# Generated by FakeRAM 2.0
VERSION 5.7 ;
BUSBITCHARS "[]" ;
PROPERTYDEFINITIONS
  MACRO width INTEGER ;
  MACRO depth INTEGER ;
  MACRO banks INTEGER ;
END PROPERTYDEFINITIONS
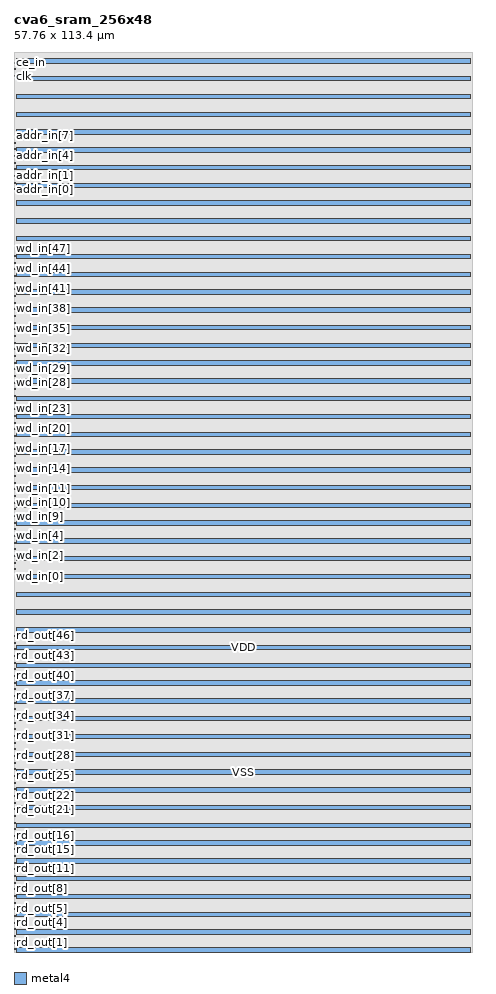
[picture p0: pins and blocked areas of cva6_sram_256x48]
MACRO cva6_sram_256x48
  PROPERTY width 48 ;
  PROPERTY depth 256 ;
  PROPERTY banks 1 ;
  FOREIGN cva6_sram_256x48 0 0 ;
  SYMMETRY X Y R90 ;
  SIZE 57.7600 BY 113.4000 ;
  CLASS BLOCK ;
  PIN rd_out[0]
    DIRECTION OUTPUT ;
    USE SIGNAL ;
    PORT
      LAYER metal4 ;
      RECT 0.00000 0.28000 0.14000 0.42000 ;
    END
  END rd_out[0]
  PIN rd_out[1]
    DIRECTION OUTPUT ;
    USE SIGNAL ;
    PORT
      LAYER metal4 ;
      RECT 0.00000 1.12000 0.14000 1.26000 ;
    END
  END rd_out[1]
  PIN rd_out[2]
    DIRECTION OUTPUT ;
    USE SIGNAL ;
    PORT
      LAYER metal4 ;
      RECT 0.00000 1.96000 0.14000 2.10000 ;
    END
  END rd_out[2]
  PIN rd_out[3]
    DIRECTION OUTPUT ;
    USE SIGNAL ;
    PORT
      LAYER metal4 ;
      RECT 0.00000 2.80000 0.14000 2.94000 ;
    END
  END rd_out[3]
  PIN rd_out[4]
    DIRECTION OUTPUT ;
    USE SIGNAL ;
    PORT
      LAYER metal4 ;
      RECT 0.00000 3.64000 0.14000 3.78000 ;
    END
  END rd_out[4]
  PIN rd_out[5]
    DIRECTION OUTPUT ;
    USE SIGNAL ;
    PORT
      LAYER metal4 ;
      RECT 0.00000 4.48000 0.14000 4.62000 ;
    END
  END rd_out[5]
  PIN rd_out[6]
    DIRECTION OUTPUT ;
    USE SIGNAL ;
    PORT
      LAYER metal4 ;
      RECT 0.00000 5.32000 0.14000 5.46000 ;
    END
  END rd_out[6]
  PIN rd_out[7]
    DIRECTION OUTPUT ;
    USE SIGNAL ;
    PORT
      LAYER metal4 ;
      RECT 0.00000 6.16000 0.14000 6.30000 ;
    END
  END rd_out[7]
  PIN rd_out[8]
    DIRECTION OUTPUT ;
    USE SIGNAL ;
    PORT
      LAYER metal4 ;
      RECT 0.00000 7.00000 0.14000 7.14000 ;
    END
  END rd_out[8]
  PIN rd_out[9]
    DIRECTION OUTPUT ;
    USE SIGNAL ;
    PORT
      LAYER metal4 ;
      RECT 0.00000 7.84000 0.14000 7.98000 ;
    END
  END rd_out[9]
  PIN rd_out[10]
    DIRECTION OUTPUT ;
    USE SIGNAL ;
    PORT
      LAYER metal4 ;
      RECT 0.00000 8.68000 0.14000 8.82000 ;
    END
  END rd_out[10]
  PIN rd_out[11]
    DIRECTION OUTPUT ;
    USE SIGNAL ;
    PORT
      LAYER metal4 ;
      RECT 0.00000 9.52000 0.14000 9.66000 ;
    END
  END rd_out[11]
  PIN rd_out[12]
    DIRECTION OUTPUT ;
    USE SIGNAL ;
    PORT
      LAYER metal4 ;
      RECT 0.00000 10.36000 0.14000 10.50000 ;
    END
  END rd_out[12]
  PIN rd_out[13]
    DIRECTION OUTPUT ;
    USE SIGNAL ;
    PORT
      LAYER metal4 ;
      RECT 0.00000 11.20000 0.14000 11.34000 ;
    END
  END rd_out[13]
  PIN rd_out[14]
    DIRECTION OUTPUT ;
    USE SIGNAL ;
    PORT
      LAYER metal4 ;
      RECT 0.00000 12.04000 0.14000 12.18000 ;
    END
  END rd_out[14]
  PIN rd_out[15]
    DIRECTION OUTPUT ;
    USE SIGNAL ;
    PORT
      LAYER metal4 ;
      RECT 0.00000 12.88000 0.14000 13.02000 ;
    END
  END rd_out[15]
  PIN rd_out[16]
    DIRECTION OUTPUT ;
    USE SIGNAL ;
    PORT
      LAYER metal4 ;
      RECT 0.00000 13.72000 0.14000 13.86000 ;
    END
  END rd_out[16]
  PIN rd_out[17]
    DIRECTION OUTPUT ;
    USE SIGNAL ;
    PORT
      LAYER metal4 ;
      RECT 0.00000 14.56000 0.14000 14.70000 ;
    END
  END rd_out[17]
  PIN rd_out[18]
    DIRECTION OUTPUT ;
    USE SIGNAL ;
    PORT
      LAYER metal4 ;
      RECT 0.00000 15.40000 0.14000 15.54000 ;
    END
  END rd_out[18]
  PIN rd_out[19]
    DIRECTION OUTPUT ;
    USE SIGNAL ;
    PORT
      LAYER metal4 ;
      RECT 0.00000 16.24000 0.14000 16.38000 ;
    END
  END rd_out[19]
  PIN rd_out[20]
    DIRECTION OUTPUT ;
    USE SIGNAL ;
    PORT
      LAYER metal4 ;
      RECT 0.00000 17.08000 0.14000 17.22000 ;
    END
  END rd_out[20]
  PIN rd_out[21]
    DIRECTION OUTPUT ;
    USE SIGNAL ;
    PORT
      LAYER metal4 ;
      RECT 0.00000 17.92000 0.14000 18.06000 ;
    END
  END rd_out[21]
  PIN rd_out[22]
    DIRECTION OUTPUT ;
    USE SIGNAL ;
    PORT
      LAYER metal4 ;
      RECT 0.00000 18.76000 0.14000 18.90000 ;
    END
  END rd_out[22]
  PIN rd_out[23]
    DIRECTION OUTPUT ;
    USE SIGNAL ;
    PORT
      LAYER metal4 ;
      RECT 0.00000 19.60000 0.14000 19.74000 ;
    END
  END rd_out[23]
  PIN rd_out[24]
    DIRECTION OUTPUT ;
    USE SIGNAL ;
    PORT
      LAYER metal4 ;
      RECT 0.00000 20.44000 0.14000 20.58000 ;
    END
  END rd_out[24]
  PIN rd_out[25]
    DIRECTION OUTPUT ;
    USE SIGNAL ;
    PORT
      LAYER metal4 ;
      RECT 0.00000 21.28000 0.14000 21.42000 ;
    END
  END rd_out[25]
  PIN rd_out[26]
    DIRECTION OUTPUT ;
    USE SIGNAL ;
    PORT
      LAYER metal4 ;
      RECT 0.00000 22.12000 0.14000 22.26000 ;
    END
  END rd_out[26]
  PIN rd_out[27]
    DIRECTION OUTPUT ;
    USE SIGNAL ;
    PORT
      LAYER metal4 ;
      RECT 0.00000 22.96000 0.14000 23.10000 ;
    END
  END rd_out[27]
  PIN rd_out[28]
    DIRECTION OUTPUT ;
    USE SIGNAL ;
    PORT
      LAYER metal4 ;
      RECT 0.00000 23.80000 0.14000 23.94000 ;
    END
  END rd_out[28]
  PIN rd_out[29]
    DIRECTION OUTPUT ;
    USE SIGNAL ;
    PORT
      LAYER metal4 ;
      RECT 0.00000 24.64000 0.14000 24.78000 ;
    END
  END rd_out[29]
  PIN rd_out[30]
    DIRECTION OUTPUT ;
    USE SIGNAL ;
    PORT
      LAYER metal4 ;
      RECT 0.00000 25.48000 0.14000 25.62000 ;
    END
  END rd_out[30]
  PIN rd_out[31]
    DIRECTION OUTPUT ;
    USE SIGNAL ;
    PORT
      LAYER metal4 ;
      RECT 0.00000 26.32000 0.14000 26.46000 ;
    END
  END rd_out[31]
  PIN rd_out[32]
    DIRECTION OUTPUT ;
    USE SIGNAL ;
    PORT
      LAYER metal4 ;
      RECT 0.00000 27.16000 0.14000 27.30000 ;
    END
  END rd_out[32]
  PIN rd_out[33]
    DIRECTION OUTPUT ;
    USE SIGNAL ;
    PORT
      LAYER metal4 ;
      RECT 0.00000 28.00000 0.14000 28.14000 ;
    END
  END rd_out[33]
  PIN rd_out[34]
    DIRECTION OUTPUT ;
    USE SIGNAL ;
    PORT
      LAYER metal4 ;
      RECT 0.00000 28.84000 0.14000 28.98000 ;
    END
  END rd_out[34]
  PIN rd_out[35]
    DIRECTION OUTPUT ;
    USE SIGNAL ;
    PORT
      LAYER metal4 ;
      RECT 0.00000 29.68000 0.14000 29.82000 ;
    END
  END rd_out[35]
  PIN rd_out[36]
    DIRECTION OUTPUT ;
    USE SIGNAL ;
    PORT
      LAYER metal4 ;
      RECT 0.00000 30.52000 0.14000 30.66000 ;
    END
  END rd_out[36]
  PIN rd_out[37]
    DIRECTION OUTPUT ;
    USE SIGNAL ;
    PORT
      LAYER metal4 ;
      RECT 0.00000 31.36000 0.14000 31.50000 ;
    END
  END rd_out[37]
  PIN rd_out[38]
    DIRECTION OUTPUT ;
    USE SIGNAL ;
    PORT
      LAYER metal4 ;
      RECT 0.00000 32.20000 0.14000 32.34000 ;
    END
  END rd_out[38]
  PIN rd_out[39]
    DIRECTION OUTPUT ;
    USE SIGNAL ;
    PORT
      LAYER metal4 ;
      RECT 0.00000 33.04000 0.14000 33.18000 ;
    END
  END rd_out[39]
  PIN rd_out[40]
    DIRECTION OUTPUT ;
    USE SIGNAL ;
    PORT
      LAYER metal4 ;
      RECT 0.00000 33.88000 0.14000 34.02000 ;
    END
  END rd_out[40]
  PIN rd_out[41]
    DIRECTION OUTPUT ;
    USE SIGNAL ;
    PORT
      LAYER metal4 ;
      RECT 0.00000 34.72000 0.14000 34.86000 ;
    END
  END rd_out[41]
  PIN rd_out[42]
    DIRECTION OUTPUT ;
    USE SIGNAL ;
    PORT
      LAYER metal4 ;
      RECT 0.00000 35.56000 0.14000 35.70000 ;
    END
  END rd_out[42]
  PIN rd_out[43]
    DIRECTION OUTPUT ;
    USE SIGNAL ;
    PORT
      LAYER metal4 ;
      RECT 0.00000 36.40000 0.14000 36.54000 ;
    END
  END rd_out[43]
  PIN rd_out[44]
    DIRECTION OUTPUT ;
    USE SIGNAL ;
    PORT
      LAYER metal4 ;
      RECT 0.00000 37.24000 0.14000 37.38000 ;
    END
  END rd_out[44]
  PIN rd_out[45]
    DIRECTION OUTPUT ;
    USE SIGNAL ;
    PORT
      LAYER metal4 ;
      RECT 0.00000 38.08000 0.14000 38.22000 ;
    END
  END rd_out[45]
  PIN rd_out[46]
    DIRECTION OUTPUT ;
    USE SIGNAL ;
    PORT
      LAYER metal4 ;
      RECT 0.00000 38.92000 0.14000 39.06000 ;
    END
  END rd_out[46]
  PIN rd_out[47]
    DIRECTION OUTPUT ;
    USE SIGNAL ;
    PORT
      LAYER metal4 ;
      RECT 0.00000 39.76000 0.14000 39.90000 ;
    END
  END rd_out[47]
  PIN wd_in[0]
    DIRECTION INPUT ;
    USE SIGNAL ;
    PORT
      LAYER metal4 ;
      RECT 0.00000 48.16000 0.14000 48.30000 ;
    END
  END wd_in[0]
  PIN wd_in[1]
    DIRECTION INPUT ;
    USE SIGNAL ;
    PORT
      LAYER metal4 ;
      RECT 0.00000 49.00000 0.14000 49.14000 ;
    END
  END wd_in[1]
  PIN wd_in[2]
    DIRECTION INPUT ;
    USE SIGNAL ;
    PORT
      LAYER metal4 ;
      RECT 0.00000 49.84000 0.14000 49.98000 ;
    END
  END wd_in[2]
  PIN wd_in[3]
    DIRECTION INPUT ;
    USE SIGNAL ;
    PORT
      LAYER metal4 ;
      RECT 0.00000 50.68000 0.14000 50.82000 ;
    END
  END wd_in[3]
  PIN wd_in[4]
    DIRECTION INPUT ;
    USE SIGNAL ;
    PORT
      LAYER metal4 ;
      RECT 0.00000 51.52000 0.14000 51.66000 ;
    END
  END wd_in[4]
  PIN wd_in[5]
    DIRECTION INPUT ;
    USE SIGNAL ;
    PORT
      LAYER metal4 ;
      RECT 0.00000 52.36000 0.14000 52.50000 ;
    END
  END wd_in[5]
  PIN wd_in[6]
    DIRECTION INPUT ;
    USE SIGNAL ;
    PORT
      LAYER metal4 ;
      RECT 0.00000 53.20000 0.14000 53.34000 ;
    END
  END wd_in[6]
  PIN wd_in[7]
    DIRECTION INPUT ;
    USE SIGNAL ;
    PORT
      LAYER metal4 ;
      RECT 0.00000 54.04000 0.14000 54.18000 ;
    END
  END wd_in[7]
  PIN wd_in[8]
    DIRECTION INPUT ;
    USE SIGNAL ;
    PORT
      LAYER metal4 ;
      RECT 0.00000 54.88000 0.14000 55.02000 ;
    END
  END wd_in[8]
  PIN wd_in[9]
    DIRECTION INPUT ;
    USE SIGNAL ;
    PORT
      LAYER metal4 ;
      RECT 0.00000 55.72000 0.14000 55.86000 ;
    END
  END wd_in[9]
  PIN wd_in[10]
    DIRECTION INPUT ;
    USE SIGNAL ;
    PORT
      LAYER metal4 ;
      RECT 0.00000 56.56000 0.14000 56.70000 ;
    END
  END wd_in[10]
  PIN wd_in[11]
    DIRECTION INPUT ;
    USE SIGNAL ;
    PORT
      LAYER metal4 ;
      RECT 0.00000 57.40000 0.14000 57.54000 ;
    END
  END wd_in[11]
  PIN wd_in[12]
    DIRECTION INPUT ;
    USE SIGNAL ;
    PORT
      LAYER metal4 ;
      RECT 0.00000 58.24000 0.14000 58.38000 ;
    END
  END wd_in[12]
  PIN wd_in[13]
    DIRECTION INPUT ;
    USE SIGNAL ;
    PORT
      LAYER metal4 ;
      RECT 0.00000 59.08000 0.14000 59.22000 ;
    END
  END wd_in[13]
  PIN wd_in[14]
    DIRECTION INPUT ;
    USE SIGNAL ;
    PORT
      LAYER metal4 ;
      RECT 0.00000 59.92000 0.14000 60.06000 ;
    END
  END wd_in[14]
  PIN wd_in[15]
    DIRECTION INPUT ;
    USE SIGNAL ;
    PORT
      LAYER metal4 ;
      RECT 0.00000 60.76000 0.14000 60.90000 ;
    END
  END wd_in[15]
  PIN wd_in[16]
    DIRECTION INPUT ;
    USE SIGNAL ;
    PORT
      LAYER metal4 ;
      RECT 0.00000 61.60000 0.14000 61.74000 ;
    END
  END wd_in[16]
  PIN wd_in[17]
    DIRECTION INPUT ;
    USE SIGNAL ;
    PORT
      LAYER metal4 ;
      RECT 0.00000 62.44000 0.14000 62.58000 ;
    END
  END wd_in[17]
  PIN wd_in[18]
    DIRECTION INPUT ;
    USE SIGNAL ;
    PORT
      LAYER metal4 ;
      RECT 0.00000 63.28000 0.14000 63.42000 ;
    END
  END wd_in[18]
  PIN wd_in[19]
    DIRECTION INPUT ;
    USE SIGNAL ;
    PORT
      LAYER metal4 ;
      RECT 0.00000 64.12000 0.14000 64.26000 ;
    END
  END wd_in[19]
  PIN wd_in[20]
    DIRECTION INPUT ;
    USE SIGNAL ;
    PORT
      LAYER metal4 ;
      RECT 0.00000 64.96000 0.14000 65.10000 ;
    END
  END wd_in[20]
  PIN wd_in[21]
    DIRECTION INPUT ;
    USE SIGNAL ;
    PORT
      LAYER metal4 ;
      RECT 0.00000 65.80000 0.14000 65.94000 ;
    END
  END wd_in[21]
  PIN wd_in[22]
    DIRECTION INPUT ;
    USE SIGNAL ;
    PORT
      LAYER metal4 ;
      RECT 0.00000 66.64000 0.14000 66.78000 ;
    END
  END wd_in[22]
  PIN wd_in[23]
    DIRECTION INPUT ;
    USE SIGNAL ;
    PORT
      LAYER metal4 ;
      RECT 0.00000 67.48000 0.14000 67.62000 ;
    END
  END wd_in[23]
  PIN wd_in[24]
    DIRECTION INPUT ;
    USE SIGNAL ;
    PORT
      LAYER metal4 ;
      RECT 0.00000 68.32000 0.14000 68.46000 ;
    END
  END wd_in[24]
  PIN wd_in[25]
    DIRECTION INPUT ;
    USE SIGNAL ;
    PORT
      LAYER metal4 ;
      RECT 0.00000 69.16000 0.14000 69.30000 ;
    END
  END wd_in[25]
  PIN wd_in[26]
    DIRECTION INPUT ;
    USE SIGNAL ;
    PORT
      LAYER metal4 ;
      RECT 0.00000 70.00000 0.14000 70.14000 ;
    END
  END wd_in[26]
  PIN wd_in[27]
    DIRECTION INPUT ;
    USE SIGNAL ;
    PORT
      LAYER metal4 ;
      RECT 0.00000 70.84000 0.14000 70.98000 ;
    END
  END wd_in[27]
  PIN wd_in[28]
    DIRECTION INPUT ;
    USE SIGNAL ;
    PORT
      LAYER metal4 ;
      RECT 0.00000 71.68000 0.14000 71.82000 ;
    END
  END wd_in[28]
  PIN wd_in[29]
    DIRECTION INPUT ;
    USE SIGNAL ;
    PORT
      LAYER metal4 ;
      RECT 0.00000 72.52000 0.14000 72.66000 ;
    END
  END wd_in[29]
  PIN wd_in[30]
    DIRECTION INPUT ;
    USE SIGNAL ;
    PORT
      LAYER metal4 ;
      RECT 0.00000 73.36000 0.14000 73.50000 ;
    END
  END wd_in[30]
  PIN wd_in[31]
    DIRECTION INPUT ;
    USE SIGNAL ;
    PORT
      LAYER metal4 ;
      RECT 0.00000 74.20000 0.14000 74.34000 ;
    END
  END wd_in[31]
  PIN wd_in[32]
    DIRECTION INPUT ;
    USE SIGNAL ;
    PORT
      LAYER metal4 ;
      RECT 0.00000 75.04000 0.14000 75.18000 ;
    END
  END wd_in[32]
  PIN wd_in[33]
    DIRECTION INPUT ;
    USE SIGNAL ;
    PORT
      LAYER metal4 ;
      RECT 0.00000 75.88000 0.14000 76.02000 ;
    END
  END wd_in[33]
  PIN wd_in[34]
    DIRECTION INPUT ;
    USE SIGNAL ;
    PORT
      LAYER metal4 ;
      RECT 0.00000 76.72000 0.14000 76.86000 ;
    END
  END wd_in[34]
  PIN wd_in[35]
    DIRECTION INPUT ;
    USE SIGNAL ;
    PORT
      LAYER metal4 ;
      RECT 0.00000 77.56000 0.14000 77.70000 ;
    END
  END wd_in[35]
  PIN wd_in[36]
    DIRECTION INPUT ;
    USE SIGNAL ;
    PORT
      LAYER metal4 ;
      RECT 0.00000 78.40000 0.14000 78.54000 ;
    END
  END wd_in[36]
  PIN wd_in[37]
    DIRECTION INPUT ;
    USE SIGNAL ;
    PORT
      LAYER metal4 ;
      RECT 0.00000 79.24000 0.14000 79.38000 ;
    END
  END wd_in[37]
  PIN wd_in[38]
    DIRECTION INPUT ;
    USE SIGNAL ;
    PORT
      LAYER metal4 ;
      RECT 0.00000 80.08000 0.14000 80.22000 ;
    END
  END wd_in[38]
  PIN wd_in[39]
    DIRECTION INPUT ;
    USE SIGNAL ;
    PORT
      LAYER metal4 ;
      RECT 0.00000 80.92000 0.14000 81.06000 ;
    END
  END wd_in[39]
  PIN wd_in[40]
    DIRECTION INPUT ;
    USE SIGNAL ;
    PORT
      LAYER metal4 ;
      RECT 0.00000 81.76000 0.14000 81.90000 ;
    END
  END wd_in[40]
  PIN wd_in[41]
    DIRECTION INPUT ;
    USE SIGNAL ;
    PORT
      LAYER metal4 ;
      RECT 0.00000 82.60000 0.14000 82.74000 ;
    END
  END wd_in[41]
  PIN wd_in[42]
    DIRECTION INPUT ;
    USE SIGNAL ;
    PORT
      LAYER metal4 ;
      RECT 0.00000 83.44000 0.14000 83.58000 ;
    END
  END wd_in[42]
  PIN wd_in[43]
    DIRECTION INPUT ;
    USE SIGNAL ;
    PORT
      LAYER metal4 ;
      RECT 0.00000 84.28000 0.14000 84.42000 ;
    END
  END wd_in[43]
  PIN wd_in[44]
    DIRECTION INPUT ;
    USE SIGNAL ;
    PORT
      LAYER metal4 ;
      RECT 0.00000 85.12000 0.14000 85.26000 ;
    END
  END wd_in[44]
  PIN wd_in[45]
    DIRECTION INPUT ;
    USE SIGNAL ;
    PORT
      LAYER metal4 ;
      RECT 0.00000 85.96000 0.14000 86.10000 ;
    END
  END wd_in[45]
  PIN wd_in[46]
    DIRECTION INPUT ;
    USE SIGNAL ;
    PORT
      LAYER metal4 ;
      RECT 0.00000 86.80000 0.14000 86.94000 ;
    END
  END wd_in[46]
  PIN wd_in[47]
    DIRECTION INPUT ;
    USE SIGNAL ;
    PORT
      LAYER metal4 ;
      RECT 0.00000 87.64000 0.14000 87.78000 ;
    END
  END wd_in[47]
  PIN addr_in[0]
    DIRECTION INPUT ;
    USE SIGNAL ;
    PORT
      LAYER metal4 ;
      RECT 0.00000 96.04000 0.14000 96.18000 ;
    END
  END addr_in[0]
  PIN addr_in[1]
    DIRECTION INPUT ;
    USE SIGNAL ;
    PORT
      LAYER metal4 ;
      RECT 0.00000 96.88000 0.14000 97.02000 ;
    END
  END addr_in[1]
  PIN addr_in[2]
    DIRECTION INPUT ;
    USE SIGNAL ;
    PORT
      LAYER metal4 ;
      RECT 0.00000 97.72000 0.14000 97.86000 ;
    END
  END addr_in[2]
  PIN addr_in[3]
    DIRECTION INPUT ;
    USE SIGNAL ;
    PORT
      LAYER metal4 ;
      RECT 0.00000 98.56000 0.14000 98.70000 ;
    END
  END addr_in[3]
  PIN addr_in[4]
    DIRECTION INPUT ;
    USE SIGNAL ;
    PORT
      LAYER metal4 ;
      RECT 0.00000 99.40000 0.14000 99.54000 ;
    END
  END addr_in[4]
  PIN addr_in[5]
    DIRECTION INPUT ;
    USE SIGNAL ;
    PORT
      LAYER metal4 ;
      RECT 0.00000 100.24000 0.14000 100.38000 ;
    END
  END addr_in[5]
  PIN addr_in[6]
    DIRECTION INPUT ;
    USE SIGNAL ;
    PORT
      LAYER metal4 ;
      RECT 0.00000 101.08000 0.14000 101.22000 ;
    END
  END addr_in[6]
  PIN addr_in[7]
    DIRECTION INPUT ;
    USE SIGNAL ;
    PORT
      LAYER metal4 ;
      RECT 0.00000 101.92000 0.14000 102.06000 ;
    END
  END addr_in[7]
  PIN we_in
    DIRECTION INPUT ;
    USE SIGNAL ;
    PORT
      LAYER metal4 ;
      RECT 0.00000 110.32000 0.14000 110.46000 ;
    END
  END we_in
  PIN clk
    DIRECTION INPUT ;
    USE SIGNAL ;
    PORT
      LAYER metal4 ;
      RECT 0.00000 111.16000 0.14000 111.30000 ;
    END
  END clk
  PIN ce_in
    DIRECTION INPUT ;
    USE SIGNAL ;
    PORT
      LAYER metal4 ;
      RECT 0.00000 112.00000 0.14000 112.14000 ;
    END
  END ce_in
  PIN VDD
    DIRECTION INOUT ;
    USE POWER ;
    PORT
      LAYER metal4 ;
      RECT 0.28000 2.24000 57.48000 2.80000 ;
      RECT 0.28000 6.72000 57.48000 7.28000 ;
      RECT 0.28000 11.20000 57.48000 11.76000 ;
      RECT 0.28000 15.68000 57.48000 16.24000 ;
      RECT 0.28000 20.16000 57.48000 20.72000 ;
      RECT 0.28000 24.64000 57.48000 25.20000 ;
      RECT 0.28000 29.12000 57.48000 29.68000 ;
      RECT 0.28000 33.60000 57.48000 34.16000 ;
      RECT 0.28000 38.08000 57.48000 38.64000 ;
      RECT 0.28000 42.56000 57.48000 43.12000 ;
      RECT 0.28000 47.04000 57.48000 47.60000 ;
      RECT 0.28000 51.52000 57.48000 52.08000 ;
      RECT 0.28000 56.00000 57.48000 56.56000 ;
      RECT 0.28000 60.48000 57.48000 61.04000 ;
      RECT 0.28000 64.96000 57.48000 65.52000 ;
      RECT 0.28000 69.44000 57.48000 70.00000 ;
      RECT 0.28000 73.92000 57.48000 74.48000 ;
      RECT 0.28000 78.40000 57.48000 78.96000 ;
      RECT 0.28000 82.88000 57.48000 83.44000 ;
      RECT 0.28000 87.36000 57.48000 87.92000 ;
      RECT 0.28000 91.84000 57.48000 92.40000 ;
      RECT 0.28000 96.32000 57.48000 96.88000 ;
      RECT 0.28000 100.80000 57.48000 101.36000 ;
      RECT 0.28000 105.28000 57.48000 105.84000 ;
      RECT 0.28000 109.76000 57.48000 110.32000 ;
    END
  END VDD
  PIN VSS
    DIRECTION INOUT ;
    USE GROUND ;
    PORT
      LAYER metal4 ;
      RECT 0.28000 0.00000 57.48000 0.56000 ;
      RECT 0.28000 4.48000 57.48000 5.04000 ;
      RECT 0.28000 8.96000 57.48000 9.52000 ;
      RECT 0.28000 13.44000 57.48000 14.00000 ;
      RECT 0.28000 17.92000 57.48000 18.48000 ;
      RECT 0.28000 22.40000 57.48000 22.96000 ;
      RECT 0.28000 26.88000 57.48000 27.44000 ;
      RECT 0.28000 31.36000 57.48000 31.92000 ;
      RECT 0.28000 35.84000 57.48000 36.40000 ;
      RECT 0.28000 40.32000 57.48000 40.88000 ;
      RECT 0.28000 44.80000 57.48000 45.36000 ;
      RECT 0.28000 49.28000 57.48000 49.84000 ;
      RECT 0.28000 53.76000 57.48000 54.32000 ;
      RECT 0.28000 58.24000 57.48000 58.80000 ;
      RECT 0.28000 62.72000 57.48000 63.28000 ;
      RECT 0.28000 67.20000 57.48000 67.76000 ;
      RECT 0.28000 71.68000 57.48000 72.24000 ;
      RECT 0.28000 76.16000 57.48000 76.72000 ;
      RECT 0.28000 80.64000 57.48000 81.20000 ;
      RECT 0.28000 85.12000 57.48000 85.68000 ;
      RECT 0.28000 89.60000 57.48000 90.16000 ;
      RECT 0.28000 94.08000 57.48000 94.64000 ;
      RECT 0.28000 98.56000 57.48000 99.12000 ;
      RECT 0.28000 103.04000 57.48000 103.60000 ;
      RECT 0.28000 107.52000 57.48000 108.08000 ;
      RECT 0.28000 112.00000 57.48000 112.56000 ;
    END
  END VSS
  OBS
    LAYER metal1 ;
    RECT 0 0 57.76000 113.40000 ;
    LAYER metal2 ;
    RECT 0 0 57.76000 113.40000 ;
    LAYER metal3 ;
    RECT 0 0 57.76000 113.40000 ;
    LAYER metal4 ;
    RECT 0 0 57.76000 113.40000 ;
  END
END cva6_sram_256x48

END LIBRARY
